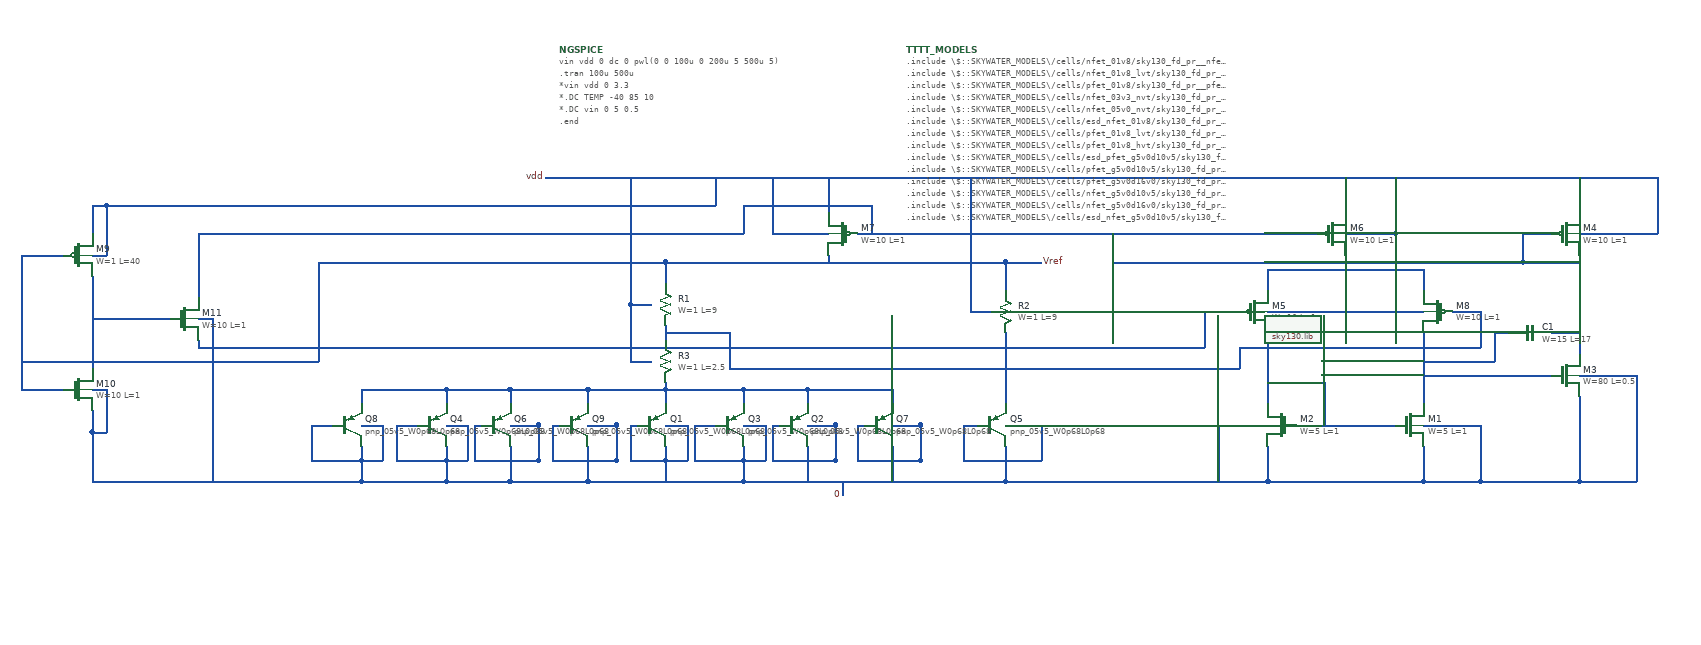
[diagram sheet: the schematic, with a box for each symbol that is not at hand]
v {xschem version=2.9.9 file_version=1.2 }
G {}
K {}
V {}
S {}
E {}
N 2650 -860 2760 -860 { lab=0}
N 3060 -940 3200 -940 { lab=#net1}
N 3020 -1040 3020 -970 { lab=#net1}
N 3240 -1040 3240 -970 { lab=#net2}
N 3100 -1000 3100 -940 { lab=#net1}
N 3020 -1000 3100 -1000 { lab=#net1}
N 3240 -910 3240 -860 { lab=0}
N 3020 -860 3240 -860 { lab=0}
N 3020 -910 3020 -860 { lab=0}
N 3240 -1070 3240 -1040 { lab=#net2}
N 3020 -1070 3020 -1040 { lab=#net1}
N 3240 -1160 3240 -1130 { lab=#net3}
N 3020 -1160 3240 -1160 { lab=#net3}
N 3020 -1160 3020 -1130 { lab=#net3}
N 3130 -1180 3130 -1160 { lab=#net3}
N 3020 -1100 3070 -1100 { lab=vdd}
N 3070 -1100 3240 -1100 { lab=vdd}
N 3240 -940 3280 -940 { lab=0}
N 2900 -860 3020 -860 { lab=0}
N 2950 -940 3020 -940 { lab=0}
N 2950 -940 2950 -860 { lab=0}
N 3280 -940 3320 -940 { lab=0}
N 3320 -940 3320 -870 { lab=0}
N 3320 -870 3320 -860 { lab=0}
N 3240 -860 3320 -860 { lab=0}
N 3240 -1010 3420 -1010 { lab=#net2}
N 2170 -1080 2170 -1060 { lab=#net4}
N 2170 -1170 2460 -1170 { lab=Vref}
N 3460 -980 3460 -860 { lab=0}
N 3320 -860 3460 -860 { lab=0}
N 3540 -1010 3540 -860 { lab=0}
N 3460 -1180 3460 -1040 { lab=#net5}
N 3460 -1210 3570 -1210 { lab=vdd}
N 3570 -1290 3570 -1210 { lab=vdd}
N 2300 -1290 3570 -1290 { lab=vdd}
N 3460 -1290 3460 -1240 { lab=vdd}
N 3130 -1290 3130 -1240 { lab=vdd}
N 3320 -1100 3320 -1050 { lab=#net4}
N 3280 -1100 3320 -1100 { lab=#net4}
N 2930 -1100 2980 -1100 { lab=#net6}
N 2650 -1170 2700 -1170 { lab=Vref}
N 3420 -1070 3460 -1070 { lab=#net5}
N 3130 -1210 3200 -1210 { lab=vdd}
N 3200 -1210 3200 -1100 { lab=vdd}
N 3200 -1290 3200 -1210 { lab=vdd}
N 3380 -1210 3430 -1210 { lab=#net5}
N 2800 -1170 3380 -1170 { lab=#net5}
N 2170 -1170 2170 -1160 { lab=Vref}
N 2170 -1160 2170 -1140 { lab=Vref}
N 2650 -1070 2650 -1030 { lab=#net6}
N 2650 -1170 2650 -1130 { lab=Vref}
N 2280 -940 2310 -940 { lab=0}
N 2310 -940 2310 -890 { lab=0}
N 2280 -890 2310 -890 { lab=0}
N 2280 -910 2280 -890 { lab=0}
N 2280 -890 2280 -860 { lab=0}
N 2460 -1170 2650 -1170 { lab=Vref}
N 2650 -1030 2650 -970 { lab=#net6}
N 2590 -940 2610 -940 { lab=0}
N 2590 -940 2590 -890 { lab=0}
N 2590 -890 2700 -890 { lab=0}
N 2700 -940 2700 -890 { lab=0}
N 2650 -940 2700 -940 { lab=0}
N 2650 -910 2650 -890 { lab=0}
N 2650 -890 2650 -860 { lab=0}
N 2280 -990 2280 -970 { lab=#net7}
N 2930 -1100 2930 -1050 { lab=#net6}
N 2650 -1050 2930 -1050 { lab=#net6}
N 2980 -1050 3320 -1050 { lab=#net4}
N 2980 -1050 2980 -1020 { lab=#net4}
N 2260 -1020 2980 -1020 { lab=#net4}
N 2260 -1070 2260 -1020 { lab=#net4}
N 2170 -1070 2260 -1070 { lab=#net4}
N 2400 -1180 2400 -1170 { lab=Vref}
N 2400 -1290 2400 -1240 { lab=vdd}
N 2440 -1210 3090 -1210 { lab=#net5}
N 3380 -1170 3460 -1170 { lab=#net5}
N 3380 -1210 3380 -1170 { lab=#net5}
N 3460 -1010 3540 -1010 { lab=0}
N 3460 -860 3540 -860 { lab=0}
N 2320 -1210 2400 -1210 { lab=vdd}
N 2320 -1290 2320 -1210 { lab=vdd}
N 2800 -1210 2800 -1170 { lab=#net5}
N 2010 -940 2020 -940 { lab=0}
N 2010 -940 2010 -890 { lab=0}
N 2010 -890 2100 -890 { lab=0}
N 2100 -940 2100 -890 { lab=0}
N 2060 -940 2100 -940 { lab=0}
N 2060 -910 2060 -890 { lab=0}
N 2060 -890 2060 -860 { lab=0}
N 2060 -990 2060 -970 { lab=#net7}
N 2060 -990 2170 -990 { lab=#net7}
N 2210 -940 2240 -940 { lab=0}
N 2210 -940 2210 -890 { lab=0}
N 2210 -890 2280 -890 { lab=0}
N 2060 -860 2280 -860 { lab=0}
N 2170 -990 2280 -990 { lab=#net7}
N 2170 -1000 2170 -990 { lab=#net7}
N 2280 -860 2650 -860 { lab=0}
N 2420 -860 2420 -840 { lab=0}
N 2170 -940 2200 -940 { lab=0}
N 2200 -940 2200 -890 { lab=0}
N 2170 -890 2200 -890 { lab=0}
N 2170 -910 2170 -890 { lab=0}
N 2170 -890 2170 -860 { lab=0}
N 2170 -990 2170 -970 { lab=#net7}
N 2100 -940 2100 -890 { lab=0}
N 2120 -940 2130 -940 { lab=0}
N 2120 -940 2120 -890 { lab=0}
N 2120 -890 2170 -890 { lab=0}
N 2320 -940 2330 -940 { lab=0}
N 2320 -940 2320 -890 { lab=0}
N 2320 -890 2410 -890 { lab=0}
N 2410 -940 2410 -890 { lab=0}
N 2370 -940 2410 -940 { lab=0}
N 2370 -910 2370 -890 { lab=0}
N 2370 -890 2370 -860 { lab=0}
N 2370 -990 2370 -970 { lab=#net7}
N 2410 -940 2410 -890 { lab=0}
N 2280 -990 2370 -990 { lab=#net7}
N 1860 -940 1890 -940 { lab=0}
N 1890 -940 1890 -890 { lab=0}
N 1860 -890 1890 -890 { lab=0}
N 1860 -910 1860 -890 { lab=0}
N 1860 -890 1860 -860 { lab=0}
N 1860 -990 1860 -970 { lab=#net7}
N 1790 -940 1820 -940 { lab=0}
N 1790 -940 1790 -890 { lab=0}
N 1790 -890 1860 -890 { lab=0}
N 1900 -940 1910 -940 { lab=0}
N 1900 -940 1900 -890 { lab=0}
N 1900 -890 1990 -890 { lab=0}
N 1990 -940 1990 -890 { lab=0}
N 1950 -940 1990 -940 { lab=0}
N 1950 -910 1950 -890 { lab=0}
N 1950 -890 1950 -860 { lab=0}
N 1950 -990 1950 -970 { lab=#net7}
N 1990 -940 1990 -890 { lab=0}
N 1860 -990 1950 -990 { lab=#net7}
N 1950 -860 2060 -860 { lab=0}
N 1860 -860 1950 -860 { lab=0}
N 2440 -940 2450 -940 { lab=0}
N 2440 -940 2440 -890 { lab=0}
N 2440 -890 2530 -890 { lab=0}
N 2530 -940 2530 -890 { lab=0}
N 2490 -940 2530 -940 { lab=0}
N 2490 -910 2490 -890 { lab=0}
N 2490 -990 2490 -970 { lab=#net7}
N 2530 -940 2530 -890 { lab=0}
N 2490 -890 2490 -860 { lab=0}
N 2370 -990 2490 -990 { lab=#net7}
N 1950 -990 2060 -990 { lab=#net7}
N 1740 -940 1770 -940 { lab=0}
N 1770 -940 1770 -890 { lab=0}
N 1740 -890 1770 -890 { lab=0}
N 1740 -910 1740 -890 { lab=0}
N 1740 -890 1740 -860 { lab=0}
N 1740 -990 1740 -970 { lab=#net7}
N 1670 -940 1700 -940 { lab=0}
N 1670 -940 1670 -890 { lab=0}
N 1670 -890 1740 -890 { lab=0}
N 1740 -990 1860 -990 { lab=#net7}
N 1740 -860 1860 -860 { lab=0}
N 1260 -1180 1320 -1180 { lab=Vref}
N 1260 -1180 1260 -990 { lab=Vref}
N 1260 -990 1320 -990 { lab=Vref}
N 1360 -1150 1360 -1020 { lab=#net8}
N 1360 -1180 1380 -1180 { lab=vdd}
N 1380 -1250 1380 -1180 { lab=vdd}
N 1360 -1250 1380 -1250 { lab=vdd}
N 1360 -1250 1360 -1210 { lab=vdd}
N 1380 -1250 2240 -1250 { lab=vdd}
N 2240 -1290 2240 -1250 { lab=vdd}
N 1360 -990 1380 -990 { lab=0}
N 1380 -990 1380 -930 { lab=0}
N 1360 -930 1380 -930 { lab=0}
N 1360 -960 1360 -930 { lab=0}
N 1360 -930 1360 -870 { lab=0}
N 1360 -870 1360 -860 { lab=0}
N 1360 -860 1740 -860 { lab=0}
N 1510 -1210 1510 -1120 { lab=#net5}
N 1510 -1210 2280 -1210 { lab=#net5}
N 2280 -1250 2280 -1210 { lab=#net5}
N 2280 -1250 2460 -1250 { lab=#net5}
N 2460 -1250 2460 -1210 { lab=#net5}
N 1510 -1090 1530 -1090 { lab=0}
N 1530 -1090 1530 -860 { lab=0}
N 1510 -1030 1680 -1030 { lab=Vref}
N 1680 -1170 1680 -1030 { lab=Vref}
N 1680 -1170 2170 -1170 { lab=Vref}
N 1360 -1090 1470 -1090 { lab=#net8}
N 1260 -1030 1510 -1030 { lab=Vref}
N 1510 -1050 2650 -1050 { lab=#net6}
N 1510 -1060 1510 -1050 { lab=#net6}
N 2600 -1100 2630 -1100 { lab=vdd}
N 2600 -1290 2600 -1100 { lab=vdd}
N 2000 -1290 2300 -1290 { lab=vdd}
N 2120 -1110 2150 -1110 { lab=vdd}
N 2120 -1290 2120 -1110 { lab=vdd}
N 2120 -1030 2150 -1030 { lab=vdd}
N 2120 -1110 2120 -1030 { lab=vdd}
N 3240 -1030 3340 -1030 { lab=#net2}
N 3340 -1070 3340 -1030 { lab=#net2}
N 3340 -1070 3360 -1070 { lab=#net2}
N 2760 -860 2900 -860 { lab=0}
C {sky130_fd_pr/pnp_05v5.sym} 2260 -940 0 0 {name=Q3
model=pnp_05v5_W0p68L0p68
spiceprefix=X
}
C {devices/lab_pin.sym} 2700 -1170 0 1 {name=l4 sig_type=std_logic lab=Vref}
C {devices/code_shown.sym} 2020 -1470 0 0 {name=NGSPICE
only_toplevel=true
value="
vin vdd 0 dc 0 pwl(0 0 100u 0 200u 5 500u 5)
.tran 100u 500u
*vin vdd 0 3.3
*.DC TEMP -40 85 10
*.DC vin 0 5 0.5
.end
" }
C {sky130_fd_pr/pnp_05v5.sym} 2630 -940 0 0 {name=Q5
model=pnp_05v5_W0p68L0p68
spiceprefix=X
}
C {devices/lab_pin.sym} 2000 -1290 0 0 {name=l2 sig_type=std_logic lab=vdd}
C {sky130_fd_pr/pnp_05v5.sym} 2040 -940 0 0 {name=Q9
model=pnp_05v5_W0p68L0p68
spiceprefix=X
}
C {devices/lab_pin.sym} 2420 -840 0 0 {name=l1 sig_type=std_logic lab=0}
C {sky130_fd_pr/pnp_05v5.sym} 2150 -940 0 0 {name=Q1
model=pnp_05v5_W0p68L0p68
spiceprefix=X
}
C {sky130_fd_pr/pnp_05v5.sym} 2350 -940 0 0 {name=Q2
model=pnp_05v5_W0p68L0p68
spiceprefix=X
}
C {sky130_fd_pr/pnp_05v5.sym} 1840 -940 0 0 {name=Q4
model=pnp_05v5_W0p68L0p68
spiceprefix=X
}
C {sky130_fd_pr/pnp_05v5.sym} 1930 -940 0 0 {name=Q6
model=pnp_05v5_W0p68L0p68
spiceprefix=X
}
C {sky130_fd_pr/pnp_05v5.sym} 2470 -940 0 0 {name=Q7
model=pnp_05v5_W0p68L0p68
spiceprefix=X
}
C {sky130_fd_pr/pnp_05v5.sym} 1720 -940 0 0 {name=Q8
model=pnp_05v5_W0p68L0p68
spiceprefix=X
}
C {sky130_fd_pr/nfet_g5v0d10v5.sym} 3220 -940 0 0 {name=M1
L=1
W=5
nf=1
mult=1
ad="'int((nf+1)/2) * W/nf * 0.29'" 
pd="'2*int((nf+1)/2) * (W/nf + 0.29)'"
as="'int((nf+2)/2) * W/nf * 0.29'" 
ps="'2*int((nf+2)/2) * (W/nf + 0.29)'"
nrd="'0.29 / W'" nrs="'0.29 / W'"
sa=0 sb=0 sd=0
model=nfet_g5v0d10v5
spiceprefix=X
}
C {sky130_fd_pr/nfet_g5v0d10v5.sym} 3040 -940 0 1 {name=M2
L=1
W=5
nf=1
mult=1
ad="'int((nf+1)/2) * W/nf * 0.29'" 
pd="'2*int((nf+1)/2) * (W/nf + 0.29)'"
as="'int((nf+2)/2) * W/nf * 0.29'" 
ps="'2*int((nf+2)/2) * (W/nf + 0.29)'"
nrd="'0.29 / W'" nrs="'0.29 / W'"
sa=0 sb=0 sd=0
model=nfet_g5v0d10v5
spiceprefix=X
}
C {sky130_fd_pr/nfet_g5v0d10v5.sym} 3440 -1010 0 0 {name=M3
L=0.5
W=80
nf=1
mult=10
ad="'int((nf+1)/2) * W/nf * 0.29'" 
pd="'2*int((nf+1)/2) * (W/nf + 0.29)'"
as="'int((nf+2)/2) * W/nf * 0.29'" 
ps="'2*int((nf+2)/2) * (W/nf + 0.29)'"
nrd="'0.29 / W'" nrs="'0.29 / W'"
sa=0 sb=0 sd=0
model=nfet_g5v0d10v5
spiceprefix=X
}
C {sky130_fd_pr/pfet_g5v0d10v5.sym} 3440 -1210 0 0 {name=M4
L=1
W=10
nf=1
mult=1
ad="'int((nf+1)/2) * W/nf * 0.29'" 
pd="'2*int((nf+1)/2) * (W/nf + 0.29)'"
as="'int((nf+2)/2) * W/nf * 0.29'" 
ps="'2*int((nf+2)/2) * (W/nf + 0.29)'"
nrd="'0.29 / W'" nrs="'0.29 / W'"
sa=0 sb=0 sd=0
model=pfet_g5v0d10v5
spiceprefix=X
}
C {sky130_fd_pr/pfet_g5v0d10v5.sym} 3000 -1100 0 0 {name=M5
L=1
W=10
nf=1
mult=1
ad="'int((nf+1)/2) * W/nf * 0.29'" 
pd="'2*int((nf+1)/2) * (W/nf + 0.29)'"
as="'int((nf+2)/2) * W/nf * 0.29'" 
ps="'2*int((nf+2)/2) * (W/nf + 0.29)'"
nrd="'0.29 / W'" nrs="'0.29 / W'"
sa=0 sb=0 sd=0
model=pfet_g5v0d10v5
spiceprefix=X
}
C {sky130_fd_pr/pfet_g5v0d10v5.sym} 3110 -1210 0 0 {name=M6
L=1
W=10
nf=1
mult=1
ad="'int((nf+1)/2) * W/nf * 0.29'" 
pd="'2*int((nf+1)/2) * (W/nf + 0.29)'"
as="'int((nf+2)/2) * W/nf * 0.29'" 
ps="'2*int((nf+2)/2) * (W/nf + 0.29)'"
nrd="'0.29 / W'" nrs="'0.29 / W'"
sa=0 sb=0 sd=0
model=pfet_g5v0d10v5
spiceprefix=X
}
C {sky130_fd_pr/pfet_g5v0d10v5.sym} 2420 -1210 0 1 {name=M7
L=1
W=10
nf=1
mult=1
ad="'int((nf+1)/2) * W/nf * 0.29'" 
pd="'2*int((nf+1)/2) * (W/nf + 0.29)'"
as="'int((nf+2)/2) * W/nf * 0.29'" 
ps="'2*int((nf+2)/2) * (W/nf + 0.29)'"
nrd="'0.29 / W'" nrs="'0.29 / W'"
sa=0 sb=0 sd=0
model=pfet_g5v0d10v5
spiceprefix=X
}
C {sky130_fd_pr/pfet_g5v0d10v5.sym} 3260 -1100 0 1 {name=M8
L=1
W=10
nf=1
mult=1
ad="'int((nf+1)/2) * W/nf * 0.29'" 
pd="'2*int((nf+1)/2) * (W/nf + 0.29)'"
as="'int((nf+2)/2) * W/nf * 0.29'" 
ps="'2*int((nf+2)/2) * (W/nf + 0.29)'"
nrd="'0.29 / W'" nrs="'0.29 / W'"
sa=0 sb=0 sd=0
model=pfet_g5v0d10v5
spiceprefix=X
}
C {sky130_fd_pr/pfet_g5v0d10v5.sym} 1340 -1180 0 0 {name=M9
L=40
W=1
nf=1
mult=1
ad="'int((nf+1)/2) * W/nf * 0.29'" 
pd="'2*int((nf+1)/2) * (W/nf + 0.29)'"
as="'int((nf+2)/2) * W/nf * 0.29'" 
ps="'2*int((nf+2)/2) * (W/nf + 0.29)'"
nrd="'0.29 / W'" nrs="'0.29 / W'"
sa=0 sb=0 sd=0
model=pfet_g5v0d10v5
spiceprefix=X
}
C {sky130_fd_pr/nfet_g5v0d10v5.sym} 1340 -990 0 0 {name=M10
L=1
W=10
nf=1
mult=1
ad="'int((nf+1)/2) * W/nf * 0.29'" 
pd="'2*int((nf+1)/2) * (W/nf + 0.29)'"
as="'int((nf+2)/2) * W/nf * 0.29'" 
ps="'2*int((nf+2)/2) * (W/nf + 0.29)'"
nrd="'0.29 / W'" nrs="'0.29 / W'"
sa=0 sb=0 sd=0
model=nfet_g5v0d10v5
spiceprefix=X
}
C {sky130_fd_pr/nfet_g5v0d10v5.sym} 1490 -1090 0 0 {name=M11
L=1
W=10
nf=1
mult=1
ad="'int((nf+1)/2) * W/nf * 0.29'" 
pd="'2*int((nf+1)/2) * (W/nf + 0.29)'"
as="'int((nf+2)/2) * W/nf * 0.29'" 
ps="'2*int((nf+2)/2) * (W/nf + 0.29)'"
nrd="'0.29 / W'" nrs="'0.29 / W'"
sa=0 sb=0 sd=0
model=nfet_g5v0d10v5
spiceprefix=X
}
C {sky130_fd_pr/res_xhigh_po.sym} 2170 -1110 0 0 {name=R1
W=1
L=9
model=res_xhigh_po
spiceprefix=X
mult=1}
C {sky130_fd_pr/res_xhigh_po.sym} 2650 -1100 0 0 {name=R2
W=1
L=9
model=res_xhigh_po
spiceprefix=X
mult=1}
C {sky130_fd_pr/res_xhigh_po.sym} 2170 -1030 0 0 {name=R3
W=1
L=2.5
model=res_xhigh_po
spiceprefix=X
mult=1}
C {sky130_fd_pr_ngspice/latest/models/sky130.lib.spice} 3170 -700 0 0 {}
C {devices/code.sym} 2510 -1470 0 0 {name=TTTT_MODELS
spice_ignore=false
only_toplevel=true
format="tcleval( @value )"
value="
.include \\\\$::SKYWATER_MODELS\\\\/cells/nfet_01v8/sky130_fd_pr__nfet_01v8__tt.corner.spice
.include \\\\$::SKYWATER_MODELS\\\\/cells/nfet_01v8_lvt/sky130_fd_pr__nfet_01v8_lvt__tt.corner.spice
.include \\\\$::SKYWATER_MODELS\\\\/cells/pfet_01v8/sky130_fd_pr__pfet_01v8__tt.corner.spice
.include \\\\$::SKYWATER_MODELS\\\\/cells/nfet_03v3_nvt/sky130_fd_pr__nfet_03v3_nvt__tt.corner.spice
.include \\\\$::SKYWATER_MODELS\\\\/cells/nfet_05v0_nvt/sky130_fd_pr__nfet_05v0_nvt__tt.corner.spice
.include \\\\$::SKYWATER_MODELS\\\\/cells/esd_nfet_01v8/sky130_fd_pr__esd_nfet_01v8__tt.corner.spice
.include \\\\$::SKYWATER_MODELS\\\\/cells/pfet_01v8_lvt/sky130_fd_pr__pfet_01v8_lvt__tt.corner.spice
.include \\\\$::SKYWATER_MODELS\\\\/cells/pfet_01v8_hvt/sky130_fd_pr__pfet_01v8_hvt__tt.corner.spice
.include \\\\$::SKYWATER_MODELS\\\\/cells/esd_pfet_g5v0d10v5/sky130_fd_pr__esd_pfet_g5v0d10v5__tt.corner.spice
.include \\\\$::SKYWATER_MODELS\\\\/cells/pfet_g5v0d10v5/sky130_fd_pr__pfet_g5v0d10v5__tt.corner.spice
.include \\\\$::SKYWATER_MODELS\\\\/cells/pfet_g5v0d16v0/sky130_fd_pr__pfet_g5v0d16v0__tt.corner.spice
.include \\\\$::SKYWATER_MODELS\\\\/cells/nfet_g5v0d10v5/sky130_fd_pr__nfet_g5v0d10v5__tt.corner.spice
.include \\\\$::SKYWATER_MODELS\\\\/cells/nfet_g5v0d16v0/sky130_fd_pr__nfet_g5v0d16v0__tt_discrete.corner.spice
.include \\\\$::SKYWATER_MODELS\\\\/cells/esd_nfet_g5v0d10v5/sky130_fd_pr__esd_nfet_g5v0d10v5__tt.corner.spice
.include \\\\$::SKYWATER_MODELS\\\\/models/corners/tt/nonfet.spice
* Mismatch parameters
.include \\\\$::SKYWATER_MODELS\\\\/cells/nfet_01v8/sky130_fd_pr__nfet_01v8__mismatch.corner.spice
.include \\\\$::SKYWATER_MODELS\\\\/cells/pfet_01v8/sky130_fd_pr__pfet_01v8__mismatch.corner.spice
.include \\\\$::SKYWATER_MODELS\\\\/cells/nfet_01v8_lvt/sky130_fd_pr__nfet_01v8_lvt__mismatch.corner.spice
.include \\\\$::SKYWATER_MODELS\\\\/cells/pfet_01v8_lvt/sky130_fd_pr__pfet_01v8_lvt__mismatch.corner.spice
.include \\\\$::SKYWATER_MODELS\\\\/cells/pfet_01v8_hvt/sky130_fd_pr__pfet_01v8_hvt__mismatch.corner.spice
.include \\\\$::SKYWATER_MODELS\\\\/cells/nfet_g5v0d10v5/sky130_fd_pr__nfet_g5v0d10v5__mismatch.corner.spice
.include \\\\$::SKYWATER_MODELS\\\\/cells/pfet_g5v0d10v5/sky130_fd_pr__pfet_g5v0d10v5__mismatch.corner.spice
.include \\\\$::SKYWATER_MODELS\\\\/cells/nfet_05v0_nvt/sky130_fd_pr__nfet_05v0_nvt__mismatch.corner.spice
.include \\\\$::SKYWATER_MODELS\\\\/cells/nfet_03v3_nvt/sky130_fd_pr__nfet_03v3_nvt__mismatch.corner.spice
* Resistor\\\\$::SKYWATER_MODELS\\\\/Capacitor
.include \\\\$::SKYWATER_MODELS\\\\/models/r+c/res_typical__cap_typical.spice
.include \\\\$::SKYWATER_MODELS\\\\/models/r+c/res_typical__cap_typical__lin.spice
* Special cells
.include \\\\$::SKYWATER_MODELS\\\\/models/corners/tt/specialized_cells.spice
* All models
.include \\\\$::SKYWATER_MODELS\\\\/models/all.spice
* Corner
.include \\\\$::SKYWATER_MODELS\\\\/models/corners/tt/rf.spice
"}
C {sky130_fd_pr/cap_mim_m3_2.sym} 3390 -1070 3 0 {name=C1 model=cap_mim_m3_2 W=15 L=17 MF=1 spiceprefix=X}
